VERSION 5.7 ;
  NOWIREEXTENSIONATPIN ON ;
  DIVIDERCHAR "/" ;
  BUSBITCHARS "[]" ;
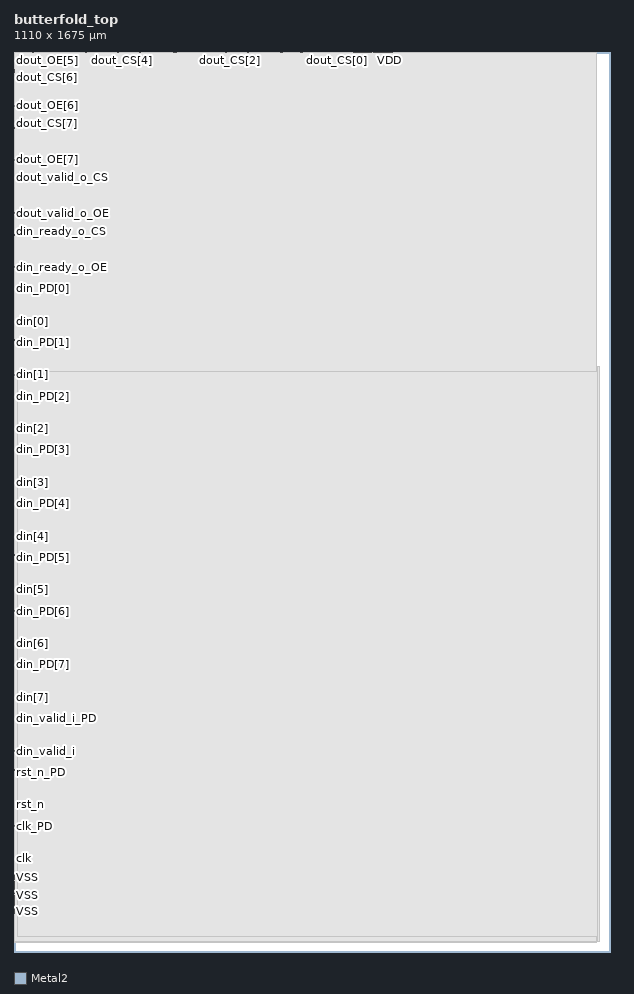
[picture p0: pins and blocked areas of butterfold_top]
MACRO butterfold_top
  CLASS BLOCK ;
  FOREIGN butterfold_top ;
  ORIGIN 0.000 0.000 ;
  SIZE 1110.000 BY 1675.000 ;
  PIN VDD
    DIRECTION INOUT ;
    USE POWER ;
    PORT
      LAYER Metal2 ;
        RECT 631.360 1674.000 640.860 1675.000 ;
    END
  END VDD
  PIN VDD
    DIRECTION INOUT ;
    USE POWER ;
    PORT
      LAYER Metal2 ;
        RECT 643.760 1674.000 654.010 1675.000 ;
    END
  END VDD
  PIN VDD
    DIRECTION INOUT ;
    USE POWER ;
    PORT
      LAYER Metal2 ;
        RECT 655.610 1674.000 665.860 1675.000 ;
    END
  END VDD
  PIN VDD
    DIRECTION INOUT ;
    USE POWER ;
    PORT
      LAYER Metal2 ;
        RECT 669.140 1674.000 679.390 1675.000 ;
    END
  END VDD
  PIN VDD
    DIRECTION INOUT ;
    USE POWER ;
    PORT
      LAYER Metal2 ;
        RECT 680.990 1674.000 691.240 1675.000 ;
    END
  END VDD
  PIN VDD
    DIRECTION INOUT ;
    USE POWER ;
    PORT
      LAYER Metal2 ;
        RECT 694.140 1674.000 703.640 1675.000 ;
    END
  END VDD
  PIN VSS
    DIRECTION INOUT ;
    USE GROUND ;
    PORT
      LAYER Metal2 ;
        RECT 0.000 71.360 1.000 80.860 ;
    END
  END VSS
  PIN VSS
    DIRECTION INOUT ;
    USE GROUND ;
    PORT
      LAYER Metal2 ;
        RECT 0.000 83.760 1.000 94.010 ;
    END
  END VSS
  PIN VSS
    DIRECTION INOUT ;
    USE GROUND ;
    PORT
      LAYER Metal2 ;
        RECT 0.000 95.610 1.000 105.860 ;
    END
  END VSS
  PIN VSS
    DIRECTION INOUT ;
    USE GROUND ;
    PORT
      LAYER Metal2 ;
        RECT 0.000 109.140 1.000 119.390 ;
    END
  END VSS
  PIN VSS
    DIRECTION INOUT ;
    USE GROUND ;
    PORT
      LAYER Metal2 ;
        RECT 0.000 120.990 1.000 131.240 ;
    END
  END VSS
  PIN VSS
    DIRECTION INOUT ;
    USE GROUND ;
    PORT
      LAYER Metal2 ;
        RECT 0.000 134.140 1.000 143.640 ;
    END
  END VSS
  PIN clk
    DIRECTION INPUT ;
    USE SIGNAL ;
    ANTENNAGATEAREA 21.647999 ;
    PORT
      LAYER Metal2 ;
        RECT 0.000 173.760 1.000 174.140 ;
    END
  END clk
  PIN clk_PD
    DIRECTION OUTPUT ;
    USE SIGNAL ;
    ANTENNADIFFAREA 0.290400 ;
    PORT
      LAYER Metal2 ;
        RECT 0.000 234.290 1.000 234.670 ;
    END
  END clk_PD
  PIN clk_PU
    DIRECTION OUTPUT ;
    USE SIGNAL ;
    ANTENNADIFFAREA 0.290400 ;
    PORT
      LAYER Metal2 ;
        RECT 0.000 238.655 1.000 239.035 ;
    END
  END clk_PU
  PIN din[0]
    DIRECTION INPUT ;
    USE SIGNAL ;
    ANTENNAGATEAREA 0.396000 ;
    PORT
      LAYER Metal2 ;
        RECT 0.000 1173.760 1.000 1174.140 ;
    END
  END din[0]
  PIN din[1]
    DIRECTION INPUT ;
    USE SIGNAL ;
    ANTENNAGATEAREA 0.396000 ;
    PORT
      LAYER Metal2 ;
        RECT 0.000 1073.760 1.000 1074.140 ;
    END
  END din[1]
  PIN din[2]
    DIRECTION INPUT ;
    USE SIGNAL ;
    ANTENNAGATEAREA 0.396000 ;
    PORT
      LAYER Metal2 ;
        RECT 0.000 973.760 1.000 974.140 ;
    END
  END din[2]
  PIN din[3]
    DIRECTION INPUT ;
    USE SIGNAL ;
    ANTENNAGATEAREA 0.396000 ;
    PORT
      LAYER Metal2 ;
        RECT 0.000 873.760 1.000 874.140 ;
    END
  END din[3]
  PIN din[4]
    DIRECTION INPUT ;
    USE SIGNAL ;
    ANTENNAGATEAREA 0.396000 ;
    PORT
      LAYER Metal2 ;
        RECT 0.000 773.760 1.000 774.140 ;
    END
  END din[4]
  PIN din[5]
    DIRECTION INPUT ;
    USE SIGNAL ;
    ANTENNAGATEAREA 0.396000 ;
    PORT
      LAYER Metal2 ;
        RECT 0.000 673.760 1.000 674.140 ;
    END
  END din[5]
  PIN din[6]
    DIRECTION INPUT ;
    USE SIGNAL ;
    ANTENNAGATEAREA 0.396000 ;
    PORT
      LAYER Metal2 ;
        RECT 0.000 573.760 1.000 574.140 ;
    END
  END din[6]
  PIN din[7]
    DIRECTION INPUT ;
    USE SIGNAL ;
    ANTENNAGATEAREA 1.249500 ;
    ANTENNADIFFAREA 0.813600 ;
    PORT
      LAYER Metal2 ;
        RECT 0.000 473.760 1.000 474.140 ;
    END
  END din[7]
  PIN din_PD[0]
    DIRECTION OUTPUT ;
    USE SIGNAL ;
    ANTENNADIFFAREA 0.290400 ;
    PORT
      LAYER Metal2 ;
        RECT 0.000 1234.290 1.000 1234.670 ;
    END
  END din_PD[0]
  PIN din_PD[1]
    DIRECTION OUTPUT ;
    USE SIGNAL ;
    ANTENNADIFFAREA 0.290400 ;
    PORT
      LAYER Metal2 ;
        RECT 0.000 1134.290 1.000 1134.670 ;
    END
  END din_PD[1]
  PIN din_PD[2]
    DIRECTION OUTPUT ;
    USE SIGNAL ;
    ANTENNADIFFAREA 0.290400 ;
    PORT
      LAYER Metal2 ;
        RECT 0.000 1034.290 1.000 1034.670 ;
    END
  END din_PD[2]
  PIN din_PD[3]
    DIRECTION OUTPUT ;
    USE SIGNAL ;
    ANTENNADIFFAREA 0.290400 ;
    PORT
      LAYER Metal2 ;
        RECT 0.000 934.290 1.000 934.670 ;
    END
  END din_PD[3]
  PIN din_PD[4]
    DIRECTION OUTPUT ;
    USE SIGNAL ;
    ANTENNADIFFAREA 0.290400 ;
    PORT
      LAYER Metal2 ;
        RECT 0.000 834.290 1.000 834.670 ;
    END
  END din_PD[4]
  PIN din_PD[5]
    DIRECTION OUTPUT ;
    USE SIGNAL ;
    ANTENNADIFFAREA 0.290400 ;
    PORT
      LAYER Metal2 ;
        RECT 0.000 734.290 1.000 734.670 ;
    END
  END din_PD[5]
  PIN din_PD[6]
    DIRECTION OUTPUT ;
    USE SIGNAL ;
    ANTENNADIFFAREA 0.290400 ;
    PORT
      LAYER Metal2 ;
        RECT 0.000 634.290 1.000 634.670 ;
    END
  END din_PD[6]
  PIN din_PD[7]
    DIRECTION OUTPUT ;
    USE SIGNAL ;
    ANTENNADIFFAREA 0.290400 ;
    PORT
      LAYER Metal2 ;
        RECT 0.000 534.290 1.000 534.670 ;
    END
  END din_PD[7]
  PIN din_PU[0]
    DIRECTION OUTPUT ;
    USE SIGNAL ;
    ANTENNADIFFAREA 0.290400 ;
    PORT
      LAYER Metal2 ;
        RECT 0.000 1238.655 1.000 1239.035 ;
    END
  END din_PU[0]
  PIN din_PU[1]
    DIRECTION OUTPUT ;
    USE SIGNAL ;
    ANTENNADIFFAREA 0.290400 ;
    PORT
      LAYER Metal2 ;
        RECT 0.000 1138.655 1.000 1139.035 ;
    END
  END din_PU[1]
  PIN din_PU[2]
    DIRECTION OUTPUT ;
    USE SIGNAL ;
    ANTENNADIFFAREA 0.290400 ;
    PORT
      LAYER Metal2 ;
        RECT 0.000 1038.655 1.000 1039.035 ;
    END
  END din_PU[2]
  PIN din_PU[3]
    DIRECTION OUTPUT ;
    USE SIGNAL ;
    ANTENNADIFFAREA 0.290400 ;
    PORT
      LAYER Metal2 ;
        RECT 0.000 938.655 1.000 939.035 ;
    END
  END din_PU[3]
  PIN din_PU[4]
    DIRECTION OUTPUT ;
    USE SIGNAL ;
    ANTENNADIFFAREA 0.290400 ;
    PORT
      LAYER Metal2 ;
        RECT 0.000 838.655 1.000 839.035 ;
    END
  END din_PU[4]
  PIN din_PU[5]
    DIRECTION OUTPUT ;
    USE SIGNAL ;
    ANTENNADIFFAREA 0.290400 ;
    PORT
      LAYER Metal2 ;
        RECT 0.000 738.655 1.000 739.035 ;
    END
  END din_PU[5]
  PIN din_PU[6]
    DIRECTION OUTPUT ;
    USE SIGNAL ;
    ANTENNADIFFAREA 0.290400 ;
    PORT
      LAYER Metal2 ;
        RECT 0.000 638.655 1.000 639.035 ;
    END
  END din_PU[6]
  PIN din_PU[7]
    DIRECTION OUTPUT ;
    USE SIGNAL ;
    ANTENNADIFFAREA 0.290400 ;
    PORT
      LAYER Metal2 ;
        RECT 0.000 538.655 1.000 539.035 ;
    END
  END din_PU[7]
  PIN din_ready_o_CS
    DIRECTION OUTPUT ;
    USE SIGNAL ;
    ANTENNADIFFAREA 0.290400 ;
    PORT
      LAYER Metal2 ;
        RECT 0.000 1341.260 1.000 1341.640 ;
    END
  END din_ready_o_CS
  PIN din_ready_o_IE
    DIRECTION OUTPUT ;
    USE SIGNAL ;
    ANTENNADIFFAREA 0.290400 ;
    PORT
      LAYER Metal2 ;
        RECT 0.000 1333.235 1.000 1333.615 ;
    END
  END din_ready_o_IE
  PIN din_ready_o_IN
    DIRECTION INPUT ;
    USE SIGNAL ;
    PORT
      LAYER Metal2 ;
        RECT 0.000 1273.760 1.000 1274.140 ;
    END
  END din_ready_o_IN
  PIN din_ready_o_OE
    DIRECTION OUTPUT ;
    USE SIGNAL ;
    ANTENNADIFFAREA 0.396000 ;
    PORT
      LAYER Metal2 ;
        RECT 0.000 1274.490 1.000 1274.870 ;
    END
  END din_ready_o_OE
  PIN din_ready_o_OUT
    DIRECTION OUTPUT ;
    USE SIGNAL ;
    ANTENNAGATEAREA 3.942500 ;
    ANTENNADIFFAREA 2.498800 ;
    PORT
      LAYER Metal2 ;
        RECT 0.000 1275.220 1.000 1275.600 ;
    END
  END din_ready_o_OUT
  PIN din_ready_o_PD
    DIRECTION OUTPUT ;
    USE SIGNAL ;
    ANTENNADIFFAREA 0.290400 ;
    PORT
      LAYER Metal2 ;
        RECT 0.000 1334.290 1.000 1334.670 ;
    END
  END din_ready_o_PD
  PIN din_ready_o_PDRV0
    DIRECTION OUTPUT ;
    USE SIGNAL ;
    ANTENNADIFFAREA 0.396000 ;
    PORT
      LAYER Metal2 ;
        RECT 0.000 1337.510 1.000 1337.890 ;
    END
  END din_ready_o_PDRV0
  PIN din_ready_o_PDRV1
    DIRECTION OUTPUT ;
    USE SIGNAL ;
    ANTENNADIFFAREA 0.396000 ;
    PORT
      LAYER Metal2 ;
        RECT 0.000 1336.800 1.000 1337.180 ;
    END
  END din_ready_o_PDRV1
  PIN din_ready_o_PU
    DIRECTION OUTPUT ;
    USE SIGNAL ;
    ANTENNADIFFAREA 0.290400 ;
    PORT
      LAYER Metal2 ;
        RECT 0.000 1338.655 1.000 1339.035 ;
    END
  END din_ready_o_PU
  PIN din_ready_o_SL
    DIRECTION OUTPUT ;
    USE SIGNAL ;
    ANTENNADIFFAREA 0.290400 ;
    PORT
      LAYER Metal2 ;
        RECT 0.000 1275.950 1.000 1276.330 ;
    END
  END din_ready_o_SL
  PIN din_valid_i
    DIRECTION INPUT ;
    USE SIGNAL ;
    ANTENNAGATEAREA 3.717500 ;
    PORT
      LAYER Metal2 ;
        RECT 0.000 373.760 1.000 374.140 ;
    END
  END din_valid_i
  PIN din_valid_i_PD
    DIRECTION OUTPUT ;
    USE SIGNAL ;
    ANTENNADIFFAREA 0.290400 ;
    PORT
      LAYER Metal2 ;
        RECT 0.000 434.290 1.000 434.670 ;
    END
  END din_valid_i_PD
  PIN din_valid_i_PU
    DIRECTION OUTPUT ;
    USE SIGNAL ;
    ANTENNADIFFAREA 0.290400 ;
    PORT
      LAYER Metal2 ;
        RECT 0.000 438.655 1.000 439.035 ;
    END
  END din_valid_i_PU
  PIN dout_CS[0]
    DIRECTION OUTPUT ;
    USE SIGNAL ;
    ANTENNADIFFAREA 0.290400 ;
    PORT
      LAYER Metal2 ;
        RECT 601.260 1674.000 601.640 1675.000 ;
    END
  END dout_CS[0]
  PIN dout_CS[1]
    DIRECTION OUTPUT ;
    USE SIGNAL ;
    ANTENNADIFFAREA 0.290400 ;
    PORT
      LAYER Metal2 ;
        RECT 501.260 1674.000 501.640 1675.000 ;
    END
  END dout_CS[1]
  PIN dout_CS[2]
    DIRECTION OUTPUT ;
    USE SIGNAL ;
    ANTENNADIFFAREA 0.290400 ;
    PORT
      LAYER Metal2 ;
        RECT 401.260 1674.000 401.640 1675.000 ;
    END
  END dout_CS[2]
  PIN dout_CS[3]
    DIRECTION OUTPUT ;
    USE SIGNAL ;
    ANTENNADIFFAREA 0.290400 ;
    PORT
      LAYER Metal2 ;
        RECT 301.260 1674.000 301.640 1675.000 ;
    END
  END dout_CS[3]
  PIN dout_CS[4]
    DIRECTION OUTPUT ;
    USE SIGNAL ;
    ANTENNADIFFAREA 0.290400 ;
    PORT
      LAYER Metal2 ;
        RECT 201.260 1674.000 201.640 1675.000 ;
    END
  END dout_CS[4]
  PIN dout_CS[5]
    DIRECTION OUTPUT ;
    USE SIGNAL ;
    ANTENNADIFFAREA 0.290400 ;
    PORT
      LAYER Metal2 ;
        RECT 101.260 1674.000 101.640 1675.000 ;
    END
  END dout_CS[5]
  PIN dout_CS[6]
    DIRECTION OUTPUT ;
    USE SIGNAL ;
    ANTENNADIFFAREA 0.290400 ;
    PORT
      LAYER Metal2 ;
        RECT 0.000 1641.260 1.000 1641.640 ;
    END
  END dout_CS[6]
  PIN dout_CS[7]
    DIRECTION OUTPUT ;
    USE SIGNAL ;
    ANTENNADIFFAREA 0.290400 ;
    PORT
      LAYER Metal2 ;
        RECT 0.000 1541.260 1.000 1541.640 ;
    END
  END dout_CS[7]
  PIN dout_IE[0]
    DIRECTION OUTPUT ;
    USE SIGNAL ;
    ANTENNADIFFAREA 0.290400 ;
    PORT
      LAYER Metal2 ;
        RECT 593.235 1674.000 593.615 1675.000 ;
    END
  END dout_IE[0]
  PIN dout_IE[1]
    DIRECTION OUTPUT ;
    USE SIGNAL ;
    ANTENNADIFFAREA 0.290400 ;
    PORT
      LAYER Metal2 ;
        RECT 493.235 1674.000 493.615 1675.000 ;
    END
  END dout_IE[1]
  PIN dout_IE[2]
    DIRECTION OUTPUT ;
    USE SIGNAL ;
    ANTENNADIFFAREA 0.290400 ;
    PORT
      LAYER Metal2 ;
        RECT 393.235 1674.000 393.615 1675.000 ;
    END
  END dout_IE[2]
  PIN dout_IE[3]
    DIRECTION OUTPUT ;
    USE SIGNAL ;
    ANTENNADIFFAREA 0.290400 ;
    PORT
      LAYER Metal2 ;
        RECT 293.235 1674.000 293.615 1675.000 ;
    END
  END dout_IE[3]
  PIN dout_IE[4]
    DIRECTION OUTPUT ;
    USE SIGNAL ;
    ANTENNADIFFAREA 0.290400 ;
    PORT
      LAYER Metal2 ;
        RECT 193.235 1674.000 193.615 1675.000 ;
    END
  END dout_IE[4]
  PIN dout_IE[5]
    DIRECTION OUTPUT ;
    USE SIGNAL ;
    ANTENNADIFFAREA 0.290400 ;
    PORT
      LAYER Metal2 ;
        RECT 93.235 1674.000 93.615 1675.000 ;
    END
  END dout_IE[5]
  PIN dout_IE[6]
    DIRECTION OUTPUT ;
    USE SIGNAL ;
    ANTENNADIFFAREA 0.290400 ;
    PORT
      LAYER Metal2 ;
        RECT 0.000 1633.235 1.000 1633.615 ;
    END
  END dout_IE[6]
  PIN dout_IE[7]
    DIRECTION OUTPUT ;
    USE SIGNAL ;
    ANTENNADIFFAREA 0.290400 ;
    PORT
      LAYER Metal2 ;
        RECT 0.000 1533.235 1.000 1533.615 ;
    END
  END dout_IE[7]
  PIN dout_IN[0]
    DIRECTION INPUT ;
    USE SIGNAL ;
    PORT
      LAYER Metal2 ;
        RECT 533.760 1674.000 534.140 1675.000 ;
    END
  END dout_IN[0]
  PIN dout_IN[1]
    DIRECTION INPUT ;
    USE SIGNAL ;
    PORT
      LAYER Metal2 ;
        RECT 433.760 1674.000 434.140 1675.000 ;
    END
  END dout_IN[1]
  PIN dout_IN[2]
    DIRECTION INPUT ;
    USE SIGNAL ;
    PORT
      LAYER Metal2 ;
        RECT 333.760 1674.000 334.140 1675.000 ;
    END
  END dout_IN[2]
  PIN dout_IN[3]
    DIRECTION INPUT ;
    USE SIGNAL ;
    PORT
      LAYER Metal2 ;
        RECT 233.760 1674.000 234.140 1675.000 ;
    END
  END dout_IN[3]
  PIN dout_IN[4]
    DIRECTION INPUT ;
    USE SIGNAL ;
    PORT
      LAYER Metal2 ;
        RECT 133.760 1674.000 134.140 1675.000 ;
    END
  END dout_IN[4]
  PIN dout_IN[5]
    DIRECTION INPUT ;
    USE SIGNAL ;
    PORT
      LAYER Metal2 ;
        RECT 33.760 1674.000 34.140 1675.000 ;
    END
  END dout_IN[5]
  PIN dout_IN[6]
    DIRECTION INPUT ;
    USE SIGNAL ;
    PORT
      LAYER Metal2 ;
        RECT 0.000 1573.760 1.000 1574.140 ;
    END
  END dout_IN[6]
  PIN dout_IN[7]
    DIRECTION INPUT ;
    USE SIGNAL ;
    PORT
      LAYER Metal2 ;
        RECT 0.000 1473.760 1.000 1474.140 ;
    END
  END dout_IN[7]
  PIN dout_OE[0]
    DIRECTION OUTPUT ;
    USE SIGNAL ;
    ANTENNADIFFAREA 0.396000 ;
    PORT
      LAYER Metal2 ;
        RECT 534.490 1674.000 534.870 1675.000 ;
    END
  END dout_OE[0]
  PIN dout_OE[1]
    DIRECTION OUTPUT ;
    USE SIGNAL ;
    ANTENNADIFFAREA 0.396000 ;
    PORT
      LAYER Metal2 ;
        RECT 434.490 1674.000 434.870 1675.000 ;
    END
  END dout_OE[1]
  PIN dout_OE[2]
    DIRECTION OUTPUT ;
    USE SIGNAL ;
    ANTENNADIFFAREA 0.396000 ;
    PORT
      LAYER Metal2 ;
        RECT 334.490 1674.000 334.870 1675.000 ;
    END
  END dout_OE[2]
  PIN dout_OE[3]
    DIRECTION OUTPUT ;
    USE SIGNAL ;
    ANTENNADIFFAREA 0.396000 ;
    PORT
      LAYER Metal2 ;
        RECT 234.490 1674.000 234.870 1675.000 ;
    END
  END dout_OE[3]
  PIN dout_OE[4]
    DIRECTION OUTPUT ;
    USE SIGNAL ;
    ANTENNADIFFAREA 0.396000 ;
    PORT
      LAYER Metal2 ;
        RECT 134.490 1674.000 134.870 1675.000 ;
    END
  END dout_OE[4]
  PIN dout_OE[5]
    DIRECTION OUTPUT ;
    USE SIGNAL ;
    ANTENNADIFFAREA 0.396000 ;
    PORT
      LAYER Metal2 ;
        RECT 34.490 1674.000 34.870 1675.000 ;
    END
  END dout_OE[5]
  PIN dout_OE[6]
    DIRECTION OUTPUT ;
    USE SIGNAL ;
    ANTENNADIFFAREA 0.396000 ;
    PORT
      LAYER Metal2 ;
        RECT 0.000 1574.490 1.000 1574.870 ;
    END
  END dout_OE[6]
  PIN dout_OE[7]
    DIRECTION OUTPUT ;
    USE SIGNAL ;
    ANTENNADIFFAREA 0.396000 ;
    PORT
      LAYER Metal2 ;
        RECT 0.000 1474.490 1.000 1474.870 ;
    END
  END dout_OE[7]
  PIN dout_OUT[0]
    DIRECTION OUTPUT ;
    USE SIGNAL ;
    ANTENNADIFFAREA 1.638000 ;
    PORT
      LAYER Metal2 ;
        RECT 535.220 1674.000 535.600 1675.000 ;
    END
  END dout_OUT[0]
  PIN dout_OUT[1]
    DIRECTION OUTPUT ;
    USE SIGNAL ;
    ANTENNADIFFAREA 1.638000 ;
    PORT
      LAYER Metal2 ;
        RECT 435.220 1674.000 435.600 1675.000 ;
    END
  END dout_OUT[1]
  PIN dout_OUT[2]
    DIRECTION OUTPUT ;
    USE SIGNAL ;
    ANTENNADIFFAREA 1.755600 ;
    PORT
      LAYER Metal2 ;
        RECT 335.220 1674.000 335.600 1675.000 ;
    END
  END dout_OUT[2]
  PIN dout_OUT[3]
    DIRECTION OUTPUT ;
    USE SIGNAL ;
    ANTENNADIFFAREA 1.126400 ;
    PORT
      LAYER Metal2 ;
        RECT 235.220 1674.000 235.600 1675.000 ;
    END
  END dout_OUT[3]
  PIN dout_OUT[4]
    DIRECTION OUTPUT ;
    USE SIGNAL ;
    ANTENNADIFFAREA 1.755600 ;
    PORT
      LAYER Metal2 ;
        RECT 135.220 1674.000 135.600 1675.000 ;
    END
  END dout_OUT[4]
  PIN dout_OUT[5]
    DIRECTION OUTPUT ;
    USE SIGNAL ;
    ANTENNADIFFAREA 1.126400 ;
    PORT
      LAYER Metal2 ;
        RECT 35.220 1674.000 35.600 1675.000 ;
    END
  END dout_OUT[5]
  PIN dout_OUT[6]
    DIRECTION OUTPUT ;
    USE SIGNAL ;
    ANTENNADIFFAREA 1.638000 ;
    PORT
      LAYER Metal2 ;
        RECT 0.000 1575.220 1.000 1575.600 ;
    END
  END dout_OUT[6]
  PIN dout_OUT[7]
    DIRECTION OUTPUT ;
    USE SIGNAL ;
    ANTENNADIFFAREA 1.126400 ;
    PORT
      LAYER Metal2 ;
        RECT 0.000 1475.220 1.000 1475.600 ;
    END
  END dout_OUT[7]
  PIN dout_PDRV0[0]
    DIRECTION OUTPUT ;
    USE SIGNAL ;
    ANTENNADIFFAREA 0.396000 ;
    PORT
      LAYER Metal2 ;
        RECT 597.510 1674.000 597.890 1675.000 ;
    END
  END dout_PDRV0[0]
  PIN dout_PDRV0[1]
    DIRECTION OUTPUT ;
    USE SIGNAL ;
    ANTENNADIFFAREA 0.396000 ;
    PORT
      LAYER Metal2 ;
        RECT 497.510 1674.000 497.890 1675.000 ;
    END
  END dout_PDRV0[1]
  PIN dout_PDRV0[2]
    DIRECTION OUTPUT ;
    USE SIGNAL ;
    ANTENNADIFFAREA 0.396000 ;
    PORT
      LAYER Metal2 ;
        RECT 397.510 1674.000 397.890 1675.000 ;
    END
  END dout_PDRV0[2]
  PIN dout_PDRV0[3]
    DIRECTION OUTPUT ;
    USE SIGNAL ;
    ANTENNADIFFAREA 0.396000 ;
    PORT
      LAYER Metal2 ;
        RECT 297.510 1674.000 297.890 1675.000 ;
    END
  END dout_PDRV0[3]
  PIN dout_PDRV0[4]
    DIRECTION OUTPUT ;
    USE SIGNAL ;
    ANTENNADIFFAREA 0.396000 ;
    PORT
      LAYER Metal2 ;
        RECT 197.510 1674.000 197.890 1675.000 ;
    END
  END dout_PDRV0[4]
  PIN dout_PDRV0[5]
    DIRECTION OUTPUT ;
    USE SIGNAL ;
    ANTENNADIFFAREA 0.396000 ;
    PORT
      LAYER Metal2 ;
        RECT 97.510 1674.000 97.890 1675.000 ;
    END
  END dout_PDRV0[5]
  PIN dout_PDRV0[6]
    DIRECTION OUTPUT ;
    USE SIGNAL ;
    ANTENNADIFFAREA 0.396000 ;
    PORT
      LAYER Metal2 ;
        RECT 0.000 1637.510 1.000 1637.890 ;
    END
  END dout_PDRV0[6]
  PIN dout_PDRV0[7]
    DIRECTION OUTPUT ;
    USE SIGNAL ;
    ANTENNADIFFAREA 0.396000 ;
    PORT
      LAYER Metal2 ;
        RECT 0.000 1537.510 1.000 1537.890 ;
    END
  END dout_PDRV0[7]
  PIN dout_PDRV1[0]
    DIRECTION OUTPUT ;
    USE SIGNAL ;
    ANTENNADIFFAREA 0.396000 ;
    PORT
      LAYER Metal2 ;
        RECT 596.800 1674.000 597.180 1675.000 ;
    END
  END dout_PDRV1[0]
  PIN dout_PDRV1[1]
    DIRECTION OUTPUT ;
    USE SIGNAL ;
    ANTENNADIFFAREA 0.396000 ;
    PORT
      LAYER Metal2 ;
        RECT 496.800 1674.000 497.180 1675.000 ;
    END
  END dout_PDRV1[1]
  PIN dout_PDRV1[2]
    DIRECTION OUTPUT ;
    USE SIGNAL ;
    ANTENNADIFFAREA 0.396000 ;
    PORT
      LAYER Metal2 ;
        RECT 396.800 1674.000 397.180 1675.000 ;
    END
  END dout_PDRV1[2]
  PIN dout_PDRV1[3]
    DIRECTION OUTPUT ;
    USE SIGNAL ;
    ANTENNADIFFAREA 0.396000 ;
    PORT
      LAYER Metal2 ;
        RECT 296.800 1674.000 297.180 1675.000 ;
    END
  END dout_PDRV1[3]
  PIN dout_PDRV1[4]
    DIRECTION OUTPUT ;
    USE SIGNAL ;
    ANTENNADIFFAREA 0.396000 ;
    PORT
      LAYER Metal2 ;
        RECT 196.800 1674.000 197.180 1675.000 ;
    END
  END dout_PDRV1[4]
  PIN dout_PDRV1[5]
    DIRECTION OUTPUT ;
    USE SIGNAL ;
    ANTENNADIFFAREA 0.396000 ;
    PORT
      LAYER Metal2 ;
        RECT 96.800 1674.000 97.180 1675.000 ;
    END
  END dout_PDRV1[5]
  PIN dout_PDRV1[6]
    DIRECTION OUTPUT ;
    USE SIGNAL ;
    ANTENNADIFFAREA 0.396000 ;
    PORT
      LAYER Metal2 ;
        RECT 0.000 1636.800 1.000 1637.180 ;
    END
  END dout_PDRV1[6]
  PIN dout_PDRV1[7]
    DIRECTION OUTPUT ;
    USE SIGNAL ;
    ANTENNADIFFAREA 0.396000 ;
    PORT
      LAYER Metal2 ;
        RECT 0.000 1536.800 1.000 1537.180 ;
    END
  END dout_PDRV1[7]
  PIN dout_PD[0]
    DIRECTION OUTPUT ;
    USE SIGNAL ;
    ANTENNADIFFAREA 0.290400 ;
    PORT
      LAYER Metal2 ;
        RECT 594.290 1674.000 594.670 1675.000 ;
    END
  END dout_PD[0]
  PIN dout_PD[1]
    DIRECTION OUTPUT ;
    USE SIGNAL ;
    ANTENNADIFFAREA 0.290400 ;
    PORT
      LAYER Metal2 ;
        RECT 494.290 1674.000 494.670 1675.000 ;
    END
  END dout_PD[1]
  PIN dout_PD[2]
    DIRECTION OUTPUT ;
    USE SIGNAL ;
    ANTENNADIFFAREA 0.290400 ;
    PORT
      LAYER Metal2 ;
        RECT 394.290 1674.000 394.670 1675.000 ;
    END
  END dout_PD[2]
  PIN dout_PD[3]
    DIRECTION OUTPUT ;
    USE SIGNAL ;
    ANTENNADIFFAREA 0.290400 ;
    PORT
      LAYER Metal2 ;
        RECT 294.290 1674.000 294.670 1675.000 ;
    END
  END dout_PD[3]
  PIN dout_PD[4]
    DIRECTION OUTPUT ;
    USE SIGNAL ;
    ANTENNADIFFAREA 0.290400 ;
    PORT
      LAYER Metal2 ;
        RECT 194.290 1674.000 194.670 1675.000 ;
    END
  END dout_PD[4]
  PIN dout_PD[5]
    DIRECTION OUTPUT ;
    USE SIGNAL ;
    ANTENNADIFFAREA 0.290400 ;
    PORT
      LAYER Metal2 ;
        RECT 94.290 1674.000 94.670 1675.000 ;
    END
  END dout_PD[5]
  PIN dout_PD[6]
    DIRECTION OUTPUT ;
    USE SIGNAL ;
    ANTENNADIFFAREA 0.290400 ;
    PORT
      LAYER Metal2 ;
        RECT 0.000 1634.290 1.000 1634.670 ;
    END
  END dout_PD[6]
  PIN dout_PD[7]
    DIRECTION OUTPUT ;
    USE SIGNAL ;
    ANTENNADIFFAREA 0.290400 ;
    PORT
      LAYER Metal2 ;
        RECT 0.000 1534.290 1.000 1534.670 ;
    END
  END dout_PD[7]
  PIN dout_PU[0]
    DIRECTION OUTPUT ;
    USE SIGNAL ;
    ANTENNADIFFAREA 0.290400 ;
    PORT
      LAYER Metal2 ;
        RECT 598.655 1674.000 599.035 1675.000 ;
    END
  END dout_PU[0]
  PIN dout_PU[1]
    DIRECTION OUTPUT ;
    USE SIGNAL ;
    ANTENNADIFFAREA 0.290400 ;
    PORT
      LAYER Metal2 ;
        RECT 498.655 1674.000 499.035 1675.000 ;
    END
  END dout_PU[1]
  PIN dout_PU[2]
    DIRECTION OUTPUT ;
    USE SIGNAL ;
    ANTENNADIFFAREA 0.290400 ;
    PORT
      LAYER Metal2 ;
        RECT 398.655 1674.000 399.035 1675.000 ;
    END
  END dout_PU[2]
  PIN dout_PU[3]
    DIRECTION OUTPUT ;
    USE SIGNAL ;
    ANTENNADIFFAREA 0.290400 ;
    PORT
      LAYER Metal2 ;
        RECT 298.655 1674.000 299.035 1675.000 ;
    END
  END dout_PU[3]
  PIN dout_PU[4]
    DIRECTION OUTPUT ;
    USE SIGNAL ;
    ANTENNADIFFAREA 0.290400 ;
    PORT
      LAYER Metal2 ;
        RECT 198.655 1674.000 199.035 1675.000 ;
    END
  END dout_PU[4]
  PIN dout_PU[5]
    DIRECTION OUTPUT ;
    USE SIGNAL ;
    ANTENNADIFFAREA 0.290400 ;
    PORT
      LAYER Metal2 ;
        RECT 98.655 1674.000 99.035 1675.000 ;
    END
  END dout_PU[5]
  PIN dout_PU[6]
    DIRECTION OUTPUT ;
    USE SIGNAL ;
    ANTENNADIFFAREA 0.290400 ;
    PORT
      LAYER Metal2 ;
        RECT 0.000 1638.655 1.000 1639.035 ;
    END
  END dout_PU[6]
  PIN dout_PU[7]
    DIRECTION OUTPUT ;
    USE SIGNAL ;
    ANTENNADIFFAREA 0.290400 ;
    PORT
      LAYER Metal2 ;
        RECT 0.000 1538.655 1.000 1539.035 ;
    END
  END dout_PU[7]
  PIN dout_SL[0]
    DIRECTION OUTPUT ;
    USE SIGNAL ;
    ANTENNADIFFAREA 0.290400 ;
    PORT
      LAYER Metal2 ;
        RECT 535.950 1674.000 536.330 1675.000 ;
    END
  END dout_SL[0]
  PIN dout_SL[1]
    DIRECTION OUTPUT ;
    USE SIGNAL ;
    ANTENNADIFFAREA 0.290400 ;
    PORT
      LAYER Metal2 ;
        RECT 435.950 1674.000 436.330 1675.000 ;
    END
  END dout_SL[1]
  PIN dout_SL[2]
    DIRECTION OUTPUT ;
    USE SIGNAL ;
    ANTENNADIFFAREA 0.290400 ;
    PORT
      LAYER Metal2 ;
        RECT 335.950 1674.000 336.330 1675.000 ;
    END
  END dout_SL[2]
  PIN dout_SL[3]
    DIRECTION OUTPUT ;
    USE SIGNAL ;
    ANTENNADIFFAREA 0.290400 ;
    PORT
      LAYER Metal2 ;
        RECT 235.950 1674.000 236.330 1675.000 ;
    END
  END dout_SL[3]
  PIN dout_SL[4]
    DIRECTION OUTPUT ;
    USE SIGNAL ;
    ANTENNADIFFAREA 0.290400 ;
    PORT
      LAYER Metal2 ;
        RECT 135.950 1674.000 136.330 1675.000 ;
    END
  END dout_SL[4]
  PIN dout_SL[5]
    DIRECTION OUTPUT ;
    USE SIGNAL ;
    ANTENNADIFFAREA 0.290400 ;
    PORT
      LAYER Metal2 ;
        RECT 35.950 1674.000 36.330 1675.000 ;
    END
  END dout_SL[5]
  PIN dout_SL[6]
    DIRECTION OUTPUT ;
    USE SIGNAL ;
    ANTENNADIFFAREA 0.290400 ;
    PORT
      LAYER Metal2 ;
        RECT 0.000 1575.950 1.000 1576.330 ;
    END
  END dout_SL[6]
  PIN dout_SL[7]
    DIRECTION OUTPUT ;
    USE SIGNAL ;
    ANTENNADIFFAREA 0.290400 ;
    PORT
      LAYER Metal2 ;
        RECT 0.000 1475.950 1.000 1476.330 ;
    END
  END dout_SL[7]
  PIN dout_valid_o_CS
    DIRECTION OUTPUT ;
    USE SIGNAL ;
    ANTENNADIFFAREA 0.290400 ;
    PORT
      LAYER Metal2 ;
        RECT 0.000 1441.260 1.000 1441.640 ;
    END
  END dout_valid_o_CS
  PIN dout_valid_o_IE
    DIRECTION OUTPUT ;
    USE SIGNAL ;
    ANTENNADIFFAREA 0.290400 ;
    PORT
      LAYER Metal2 ;
        RECT 0.000 1433.235 1.000 1433.615 ;
    END
  END dout_valid_o_IE
  PIN dout_valid_o_IN
    DIRECTION INPUT ;
    USE SIGNAL ;
    PORT
      LAYER Metal2 ;
        RECT 0.000 1373.760 1.000 1374.140 ;
    END
  END dout_valid_o_IN
  PIN dout_valid_o_OE
    DIRECTION OUTPUT ;
    USE SIGNAL ;
    ANTENNADIFFAREA 0.396000 ;
    PORT
      LAYER Metal2 ;
        RECT 0.000 1374.490 1.000 1374.870 ;
    END
  END dout_valid_o_OE
  PIN dout_valid_o_OUT
    DIRECTION OUTPUT ;
    USE SIGNAL ;
    ANTENNADIFFAREA 1.982400 ;
    PORT
      LAYER Metal2 ;
        RECT 0.000 1375.220 1.000 1375.600 ;
    END
  END dout_valid_o_OUT
  PIN dout_valid_o_PD
    DIRECTION OUTPUT ;
    USE SIGNAL ;
    ANTENNADIFFAREA 0.290400 ;
    PORT
      LAYER Metal2 ;
        RECT 0.000 1434.290 1.000 1434.670 ;
    END
  END dout_valid_o_PD
  PIN dout_valid_o_PDRV0
    DIRECTION OUTPUT ;
    USE SIGNAL ;
    ANTENNADIFFAREA 0.396000 ;
    PORT
      LAYER Metal2 ;
        RECT 0.000 1437.510 1.000 1437.890 ;
    END
  END dout_valid_o_PDRV0
  PIN dout_valid_o_PDRV1
    DIRECTION OUTPUT ;
    USE SIGNAL ;
    ANTENNADIFFAREA 0.396000 ;
    PORT
      LAYER Metal2 ;
        RECT 0.000 1436.800 1.000 1437.180 ;
    END
  END dout_valid_o_PDRV1
  PIN dout_valid_o_PU
    DIRECTION OUTPUT ;
    USE SIGNAL ;
    ANTENNADIFFAREA 0.290400 ;
    PORT
      LAYER Metal2 ;
        RECT 0.000 1438.655 1.000 1439.035 ;
    END
  END dout_valid_o_PU
  PIN dout_valid_o_SL
    DIRECTION OUTPUT ;
    USE SIGNAL ;
    ANTENNADIFFAREA 0.290400 ;
    PORT
      LAYER Metal2 ;
        RECT 0.000 1375.950 1.000 1376.330 ;
    END
  END dout_valid_o_SL
  PIN rst_n
    DIRECTION INPUT ;
    USE SIGNAL ;
    ANTENNAGATEAREA 2681.698975 ;
    PORT
      LAYER Metal2 ;
        RECT 0.000 273.760 1.000 274.140 ;
    END
  END rst_n
  PIN rst_n_PD
    DIRECTION OUTPUT ;
    USE SIGNAL ;
    ANTENNADIFFAREA 0.290400 ;
    PORT
      LAYER Metal2 ;
        RECT 0.000 334.290 1.000 334.670 ;
    END
  END rst_n_PD
  PIN rst_n_PU
    DIRECTION OUTPUT ;
    USE SIGNAL ;
    ANTENNADIFFAREA 0.290400 ;
    PORT
      LAYER Metal2 ;
        RECT 0.000 338.655 1.000 339.035 ;
    END
  END rst_n_PU
  OBS
      LAYER Nwell ;
        RECT 3.790 19.730 1088.770 1089.070 ;
      LAYER Metal1 ;
        RECT 6.720 19.710 1085.840 1089.090 ;
      LAYER Metal2 ;
        RECT 0.140 1673.700 33.460 1675.000 ;
        RECT 36.630 1673.700 92.935 1675.000 ;
        RECT 93.915 1673.700 93.990 1675.000 ;
        RECT 94.970 1673.700 96.500 1675.000 ;
        RECT 98.190 1673.700 98.355 1675.000 ;
        RECT 99.335 1673.700 100.960 1675.000 ;
        RECT 101.940 1673.700 133.460 1675.000 ;
        RECT 136.630 1673.700 192.935 1675.000 ;
        RECT 193.915 1673.700 193.990 1675.000 ;
        RECT 194.970 1673.700 196.500 1675.000 ;
        RECT 198.190 1673.700 198.355 1675.000 ;
        RECT 199.335 1673.700 200.960 1675.000 ;
        RECT 201.940 1673.700 233.460 1675.000 ;
        RECT 236.630 1673.700 292.935 1675.000 ;
        RECT 293.915 1673.700 293.990 1675.000 ;
        RECT 294.970 1673.700 296.500 1675.000 ;
        RECT 298.190 1673.700 298.355 1675.000 ;
        RECT 299.335 1673.700 300.960 1675.000 ;
        RECT 301.940 1673.700 333.460 1675.000 ;
        RECT 336.630 1673.700 392.935 1675.000 ;
        RECT 393.915 1673.700 393.990 1675.000 ;
        RECT 394.970 1673.700 396.500 1675.000 ;
        RECT 398.190 1673.700 398.355 1675.000 ;
        RECT 399.335 1673.700 400.960 1675.000 ;
        RECT 401.940 1673.700 433.460 1675.000 ;
        RECT 436.630 1673.700 492.935 1675.000 ;
        RECT 493.915 1673.700 493.990 1675.000 ;
        RECT 494.970 1673.700 496.500 1675.000 ;
        RECT 498.190 1673.700 498.355 1675.000 ;
        RECT 499.335 1673.700 500.960 1675.000 ;
        RECT 501.940 1673.700 533.460 1675.000 ;
        RECT 536.630 1673.700 592.935 1675.000 ;
        RECT 593.915 1673.700 593.990 1675.000 ;
        RECT 594.970 1673.700 596.500 1675.000 ;
        RECT 598.190 1673.700 598.355 1675.000 ;
        RECT 599.335 1673.700 600.960 1675.000 ;
        RECT 601.940 1673.700 631.060 1675.000 ;
        RECT 641.160 1673.700 643.460 1675.000 ;
        RECT 654.310 1673.700 655.310 1675.000 ;
        RECT 666.160 1673.700 668.840 1675.000 ;
        RECT 679.690 1673.700 680.690 1675.000 ;
        RECT 691.540 1673.700 693.840 1675.000 ;
        RECT 703.940 1673.700 1084.020 1675.000 ;
        RECT 0.140 1641.940 1084.020 1673.700 ;
        RECT 1.300 1640.960 1084.020 1641.940 ;
        RECT 0.140 1639.335 1084.020 1640.960 ;
        RECT 1.300 1638.355 1084.020 1639.335 ;
        RECT 0.140 1638.190 1084.020 1638.355 ;
        RECT 1.300 1636.500 1084.020 1638.190 ;
        RECT 0.140 1634.970 1084.020 1636.500 ;
        RECT 1.300 1633.990 1084.020 1634.970 ;
        RECT 0.140 1633.915 1084.020 1633.990 ;
        RECT 1.300 1632.935 1084.020 1633.915 ;
        RECT 0.140 1576.630 1084.020 1632.935 ;
        RECT 1.300 1573.460 1084.020 1576.630 ;
        RECT 0.140 1541.940 1084.020 1573.460 ;
        RECT 1.300 1540.960 1084.020 1541.940 ;
        RECT 0.140 1539.335 1084.020 1540.960 ;
        RECT 1.300 1538.355 1084.020 1539.335 ;
        RECT 0.140 1538.190 1084.020 1538.355 ;
        RECT 1.300 1536.500 1084.020 1538.190 ;
        RECT 0.140 1534.970 1084.020 1536.500 ;
        RECT 1.300 1533.990 1084.020 1534.970 ;
        RECT 0.140 1533.915 1084.020 1533.990 ;
        RECT 1.300 1532.935 1084.020 1533.915 ;
        RECT 0.140 1476.630 1084.020 1532.935 ;
        RECT 1.300 1473.460 1084.020 1476.630 ;
        RECT 0.140 1441.940 1084.020 1473.460 ;
        RECT 1.300 1440.960 1084.020 1441.940 ;
        RECT 0.140 1439.335 1084.020 1440.960 ;
        RECT 1.300 1438.355 1084.020 1439.335 ;
        RECT 0.140 1438.190 1084.020 1438.355 ;
        RECT 1.300 1436.500 1084.020 1438.190 ;
        RECT 0.140 1434.970 1084.020 1436.500 ;
        RECT 1.300 1433.990 1084.020 1434.970 ;
        RECT 0.140 1433.915 1084.020 1433.990 ;
        RECT 1.300 1432.935 1084.020 1433.915 ;
        RECT 0.140 1376.630 1084.020 1432.935 ;
        RECT 1.300 1373.460 1084.020 1376.630 ;
        RECT 0.140 1341.940 1084.020 1373.460 ;
        RECT 1.300 1340.960 1084.020 1341.940 ;
        RECT 0.140 1339.335 1084.020 1340.960 ;
        RECT 1.300 1338.355 1084.020 1339.335 ;
        RECT 0.140 1338.190 1084.020 1338.355 ;
        RECT 1.300 1336.500 1084.020 1338.190 ;
        RECT 0.140 1334.970 1084.020 1336.500 ;
        RECT 1.300 1333.990 1084.020 1334.970 ;
        RECT 0.140 1333.915 1084.020 1333.990 ;
        RECT 1.300 1332.935 1084.020 1333.915 ;
        RECT 0.140 1276.630 1084.020 1332.935 ;
        RECT 1.300 1273.460 1084.020 1276.630 ;
        RECT 0.140 1239.335 1084.020 1273.460 ;
        RECT 1.300 1238.355 1084.020 1239.335 ;
        RECT 0.140 1234.970 1084.020 1238.355 ;
        RECT 1.300 1233.990 1084.020 1234.970 ;
        RECT 0.140 1174.440 1084.020 1233.990 ;
        RECT 1.300 1173.460 1084.020 1174.440 ;
        RECT 0.140 1139.335 1084.020 1173.460 ;
        RECT 1.300 1138.355 1084.020 1139.335 ;
        RECT 0.140 1134.970 1084.020 1138.355 ;
        RECT 1.300 1133.990 1084.020 1134.970 ;
        RECT 0.140 1074.440 1084.020 1133.990 ;
        RECT 1.300 1073.460 1084.020 1074.440 ;
        RECT 0.140 1039.335 1084.020 1073.460 ;
        RECT 1.300 1038.355 1084.020 1039.335 ;
        RECT 0.140 1034.970 1084.020 1038.355 ;
        RECT 1.300 1033.990 1084.020 1034.970 ;
        RECT 0.140 974.440 1084.020 1033.990 ;
        RECT 1.300 973.460 1084.020 974.440 ;
        RECT 0.140 939.335 1084.020 973.460 ;
        RECT 1.300 938.355 1084.020 939.335 ;
        RECT 0.140 934.970 1084.020 938.355 ;
        RECT 1.300 933.990 1084.020 934.970 ;
        RECT 0.140 874.440 1084.020 933.990 ;
        RECT 1.300 873.460 1084.020 874.440 ;
        RECT 0.140 839.335 1084.020 873.460 ;
        RECT 1.300 838.355 1084.020 839.335 ;
        RECT 0.140 834.970 1084.020 838.355 ;
        RECT 1.300 833.990 1084.020 834.970 ;
        RECT 0.140 774.440 1084.020 833.990 ;
        RECT 1.300 773.460 1084.020 774.440 ;
        RECT 0.140 739.335 1084.020 773.460 ;
        RECT 1.300 738.355 1084.020 739.335 ;
        RECT 0.140 734.970 1084.020 738.355 ;
        RECT 1.300 733.990 1084.020 734.970 ;
        RECT 0.140 674.440 1084.020 733.990 ;
        RECT 1.300 673.460 1084.020 674.440 ;
        RECT 0.140 639.335 1084.020 673.460 ;
        RECT 1.300 638.355 1084.020 639.335 ;
        RECT 0.140 634.970 1084.020 638.355 ;
        RECT 1.300 633.990 1084.020 634.970 ;
        RECT 0.140 574.440 1084.020 633.990 ;
        RECT 1.300 573.460 1084.020 574.440 ;
        RECT 0.140 539.335 1084.020 573.460 ;
        RECT 1.300 538.355 1084.020 539.335 ;
        RECT 0.140 534.970 1084.020 538.355 ;
        RECT 1.300 533.990 1084.020 534.970 ;
        RECT 0.140 474.440 1084.020 533.990 ;
        RECT 1.300 473.460 1084.020 474.440 ;
        RECT 0.140 439.335 1084.020 473.460 ;
        RECT 1.300 438.355 1084.020 439.335 ;
        RECT 0.140 434.970 1084.020 438.355 ;
        RECT 1.300 433.990 1084.020 434.970 ;
        RECT 0.140 374.440 1084.020 433.990 ;
        RECT 1.300 373.460 1084.020 374.440 ;
        RECT 0.140 339.335 1084.020 373.460 ;
        RECT 1.300 338.355 1084.020 339.335 ;
        RECT 0.140 334.970 1084.020 338.355 ;
        RECT 1.300 333.990 1084.020 334.970 ;
        RECT 0.140 274.440 1084.020 333.990 ;
        RECT 1.300 273.460 1084.020 274.440 ;
        RECT 0.140 239.335 1084.020 273.460 ;
        RECT 1.300 238.355 1084.020 239.335 ;
        RECT 0.140 234.970 1084.020 238.355 ;
        RECT 1.300 233.990 1084.020 234.970 ;
        RECT 0.140 174.440 1084.020 233.990 ;
        RECT 1.300 173.460 1084.020 174.440 ;
        RECT 0.140 143.940 1084.020 173.460 ;
        RECT 1.300 133.840 1084.020 143.940 ;
        RECT 0.140 131.540 1084.020 133.840 ;
        RECT 1.300 120.690 1084.020 131.540 ;
        RECT 0.140 119.690 1084.020 120.690 ;
        RECT 1.300 108.840 1084.020 119.690 ;
        RECT 0.140 106.160 1084.020 108.840 ;
        RECT 1.300 95.310 1084.020 106.160 ;
        RECT 0.140 94.310 1084.020 95.310 ;
        RECT 1.300 83.460 1084.020 94.310 ;
        RECT 0.140 81.160 1084.020 83.460 ;
        RECT 1.300 71.060 1084.020 81.160 ;
        RECT 0.140 18.570 1084.020 71.060 ;
      LAYER Metal3 ;
        RECT 0.000 18.620 1084.070 1675.000 ;
      LAYER Metal4 ;
        RECT 0.140 19.860 1083.460 1675.000 ;
      LAYER Metal5 ;
        RECT 6.720 29.030 1085.840 1080.670 ;
  END
END butterfold_top
END LIBRARY

